VERSION 5.7 ;
BUSBITCHARS "[]" ;
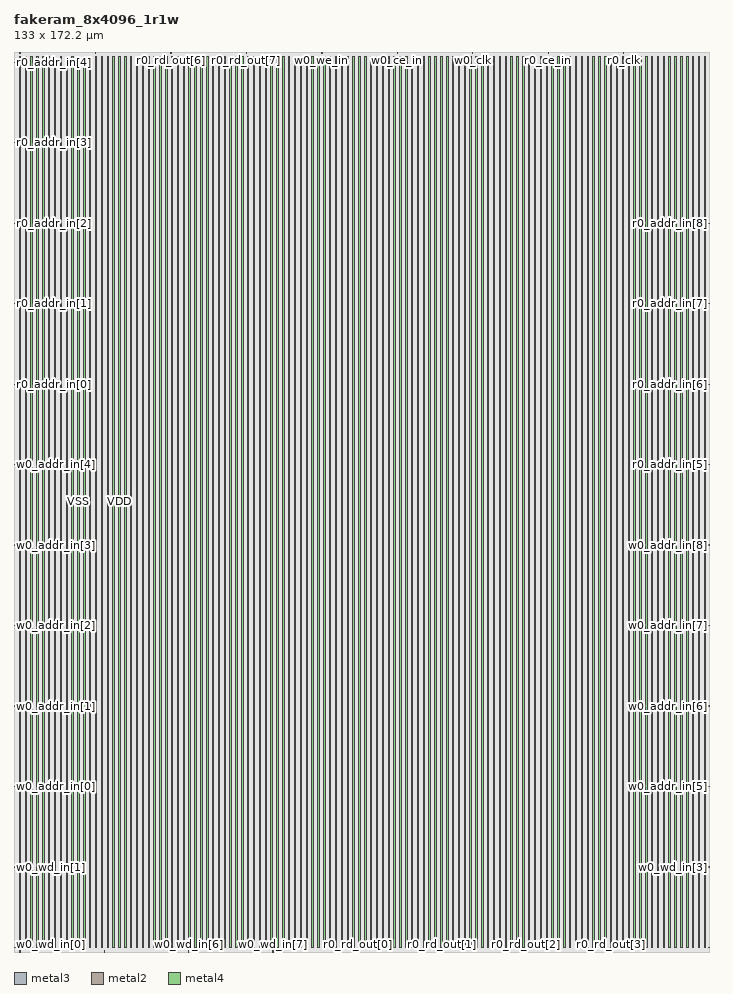
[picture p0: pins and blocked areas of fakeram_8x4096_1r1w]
MACRO fakeram_8x4096_1r1w
  FOREIGN fakeram_8x4096_1r1w 0 0 ;
  SYMMETRY X Y R90 ;
  SIZE 133.000 BY 172.200 ;
  CLASS BLOCK ;
  PIN w0_wd_in[0]
    DIRECTION INPUT ;
    USE SIGNAL ;
    SHAPE ABUTMENT ;
    PORT
      LAYER metal3 ;
      RECT 0.000 0.805 0.210 0.875 ;
    END
  END w0_wd_in[0]
  PIN w0_wd_in[1]
    DIRECTION INPUT ;
    USE SIGNAL ;
    SHAPE ABUTMENT ;
    PORT
      LAYER metal3 ;
      RECT 0.000 16.205 0.210 16.275 ;
    END
  END w0_wd_in[1]
  PIN w0_wd_in[2]
    DIRECTION INPUT ;
    USE SIGNAL ;
    SHAPE ABUTMENT ;
    PORT
      LAYER metal3 ;
      RECT 132.790 0.805 133.000 0.875 ;
    END
  END w0_wd_in[2]
  PIN w0_wd_in[3]
    DIRECTION INPUT ;
    USE SIGNAL ;
    SHAPE ABUTMENT ;
    PORT
      LAYER metal3 ;
      RECT 132.790 16.205 133.000 16.275 ;
    END
  END w0_wd_in[3]
  PIN w0_wd_in[4]
    DIRECTION INPUT ;
    USE SIGNAL ;
    SHAPE ABUTMENT ;
    PORT
      LAYER metal2 ;
      RECT 1.105 0.000 1.175 0.210 ;
    END
  END w0_wd_in[4]
  PIN w0_wd_in[5]
    DIRECTION INPUT ;
    USE SIGNAL ;
    SHAPE ABUTMENT ;
    PORT
      LAYER metal2 ;
      RECT 17.255 0.000 17.325 0.210 ;
    END
  END w0_wd_in[5]
  PIN w0_wd_in[6]
    DIRECTION INPUT ;
    USE SIGNAL ;
    SHAPE ABUTMENT ;
    PORT
      LAYER metal2 ;
      RECT 33.405 0.000 33.475 0.210 ;
    END
  END w0_wd_in[6]
  PIN w0_wd_in[7]
    DIRECTION INPUT ;
    USE SIGNAL ;
    SHAPE ABUTMENT ;
    PORT
      LAYER metal2 ;
      RECT 49.555 0.000 49.625 0.210 ;
    END
  END w0_wd_in[7]
  PIN r0_rd_out[0]
    DIRECTION OUTPUT ;
    USE SIGNAL ;
    SHAPE ABUTMENT ;
    PORT
      LAYER metal2 ;
      RECT 65.705 0.000 65.775 0.210 ;
    END
  END r0_rd_out[0]
  PIN r0_rd_out[1]
    DIRECTION OUTPUT ;
    USE SIGNAL ;
    SHAPE ABUTMENT ;
    PORT
      LAYER metal2 ;
      RECT 81.855 0.000 81.925 0.210 ;
    END
  END r0_rd_out[1]
  PIN r0_rd_out[2]
    DIRECTION OUTPUT ;
    USE SIGNAL ;
    SHAPE ABUTMENT ;
    PORT
      LAYER metal2 ;
      RECT 98.005 0.000 98.075 0.210 ;
    END
  END r0_rd_out[2]
  PIN r0_rd_out[3]
    DIRECTION OUTPUT ;
    USE SIGNAL ;
    SHAPE ABUTMENT ;
    PORT
      LAYER metal2 ;
      RECT 114.155 0.000 114.225 0.210 ;
    END
  END r0_rd_out[3]
  PIN r0_rd_out[4]
    DIRECTION OUTPUT ;
    USE SIGNAL ;
    SHAPE ABUTMENT ;
    PORT
      LAYER metal2 ;
      RECT 1.105 171.990 1.175 172.200 ;
    END
  END r0_rd_out[4]
  PIN r0_rd_out[5]
    DIRECTION OUTPUT ;
    USE SIGNAL ;
    SHAPE ABUTMENT ;
    PORT
      LAYER metal2 ;
      RECT 15.545 171.990 15.615 172.200 ;
    END
  END r0_rd_out[5]
  PIN r0_rd_out[6]
    DIRECTION OUTPUT ;
    USE SIGNAL ;
    SHAPE ABUTMENT ;
    PORT
      LAYER metal2 ;
      RECT 29.985 171.990 30.055 172.200 ;
    END
  END r0_rd_out[6]
  PIN r0_rd_out[7]
    DIRECTION OUTPUT ;
    USE SIGNAL ;
    SHAPE ABUTMENT ;
    PORT
      LAYER metal2 ;
      RECT 44.425 171.990 44.495 172.200 ;
    END
  END r0_rd_out[7]
  PIN w0_addr_in[0]
    DIRECTION INPUT ;
    USE SIGNAL ;
    SHAPE ABUTMENT ;
    PORT
      LAYER metal3 ;
      RECT 0.000 31.605 0.210 31.675 ;
    END
  END w0_addr_in[0]
  PIN w0_addr_in[1]
    DIRECTION INPUT ;
    USE SIGNAL ;
    SHAPE ABUTMENT ;
    PORT
      LAYER metal3 ;
      RECT 0.000 47.005 0.210 47.075 ;
    END
  END w0_addr_in[1]
  PIN w0_addr_in[2]
    DIRECTION INPUT ;
    USE SIGNAL ;
    SHAPE ABUTMENT ;
    PORT
      LAYER metal3 ;
      RECT 0.000 62.405 0.210 62.475 ;
    END
  END w0_addr_in[2]
  PIN w0_addr_in[3]
    DIRECTION INPUT ;
    USE SIGNAL ;
    SHAPE ABUTMENT ;
    PORT
      LAYER metal3 ;
      RECT 0.000 77.805 0.210 77.875 ;
    END
  END w0_addr_in[3]
  PIN w0_addr_in[4]
    DIRECTION INPUT ;
    USE SIGNAL ;
    SHAPE ABUTMENT ;
    PORT
      LAYER metal3 ;
      RECT 0.000 93.205 0.210 93.275 ;
    END
  END w0_addr_in[4]
  PIN w0_addr_in[5]
    DIRECTION INPUT ;
    USE SIGNAL ;
    SHAPE ABUTMENT ;
    PORT
      LAYER metal3 ;
      RECT 132.790 31.605 133.000 31.675 ;
    END
  END w0_addr_in[5]
  PIN w0_addr_in[6]
    DIRECTION INPUT ;
    USE SIGNAL ;
    SHAPE ABUTMENT ;
    PORT
      LAYER metal3 ;
      RECT 132.790 47.005 133.000 47.075 ;
    END
  END w0_addr_in[6]
  PIN w0_addr_in[7]
    DIRECTION INPUT ;
    USE SIGNAL ;
    SHAPE ABUTMENT ;
    PORT
      LAYER metal3 ;
      RECT 132.790 62.405 133.000 62.475 ;
    END
  END w0_addr_in[7]
  PIN w0_addr_in[8]
    DIRECTION INPUT ;
    USE SIGNAL ;
    SHAPE ABUTMENT ;
    PORT
      LAYER metal3 ;
      RECT 132.790 77.805 133.000 77.875 ;
    END
  END w0_addr_in[8]
  PIN r0_addr_in[0]
    DIRECTION INPUT ;
    USE SIGNAL ;
    SHAPE ABUTMENT ;
    PORT
      LAYER metal3 ;
      RECT 0.000 108.605 0.210 108.675 ;
    END
  END r0_addr_in[0]
  PIN r0_addr_in[1]
    DIRECTION INPUT ;
    USE SIGNAL ;
    SHAPE ABUTMENT ;
    PORT
      LAYER metal3 ;
      RECT 0.000 124.005 0.210 124.075 ;
    END
  END r0_addr_in[1]
  PIN r0_addr_in[2]
    DIRECTION INPUT ;
    USE SIGNAL ;
    SHAPE ABUTMENT ;
    PORT
      LAYER metal3 ;
      RECT 0.000 139.405 0.210 139.475 ;
    END
  END r0_addr_in[2]
  PIN r0_addr_in[3]
    DIRECTION INPUT ;
    USE SIGNAL ;
    SHAPE ABUTMENT ;
    PORT
      LAYER metal3 ;
      RECT 0.000 154.805 0.210 154.875 ;
    END
  END r0_addr_in[3]
  PIN r0_addr_in[4]
    DIRECTION INPUT ;
    USE SIGNAL ;
    SHAPE ABUTMENT ;
    PORT
      LAYER metal3 ;
      RECT 0.000 170.205 0.210 170.275 ;
    END
  END r0_addr_in[4]
  PIN r0_addr_in[5]
    DIRECTION INPUT ;
    USE SIGNAL ;
    SHAPE ABUTMENT ;
    PORT
      LAYER metal3 ;
      RECT 132.790 93.205 133.000 93.275 ;
    END
  END r0_addr_in[5]
  PIN r0_addr_in[6]
    DIRECTION INPUT ;
    USE SIGNAL ;
    SHAPE ABUTMENT ;
    PORT
      LAYER metal3 ;
      RECT 132.790 108.605 133.000 108.675 ;
    END
  END r0_addr_in[6]
  PIN r0_addr_in[7]
    DIRECTION INPUT ;
    USE SIGNAL ;
    SHAPE ABUTMENT ;
    PORT
      LAYER metal3 ;
      RECT 132.790 124.005 133.000 124.075 ;
    END
  END r0_addr_in[7]
  PIN r0_addr_in[8]
    DIRECTION INPUT ;
    USE SIGNAL ;
    SHAPE ABUTMENT ;
    PORT
      LAYER metal3 ;
      RECT 132.790 139.405 133.000 139.475 ;
    END
  END r0_addr_in[8]
  PIN w0_we_in
    DIRECTION INPUT ;
    USE SIGNAL ;
    SHAPE ABUTMENT ;
    PORT
      LAYER metal2 ;
      RECT 58.865 171.990 58.935 172.200 ;
    END
  END w0_we_in
  PIN w0_ce_in
    DIRECTION INPUT ;
    USE SIGNAL ;
    SHAPE ABUTMENT ;
    PORT
      LAYER metal2 ;
      RECT 73.305 171.990 73.375 172.200 ;
    END
  END w0_ce_in
  PIN w0_clk
    DIRECTION INPUT ;
    USE SIGNAL ;
    SHAPE ABUTMENT ;
    PORT
      LAYER metal2 ;
      RECT 87.745 171.990 87.815 172.200 ;
    END
  END w0_clk
  PIN r0_ce_in
    DIRECTION INPUT ;
    USE SIGNAL ;
    SHAPE ABUTMENT ;
    PORT
      LAYER metal2 ;
      RECT 102.185 171.990 102.255 172.200 ;
    END
  END r0_ce_in
  PIN r0_clk
    DIRECTION INPUT ;
    USE SIGNAL ;
    SHAPE ABUTMENT ;
    PORT
      LAYER metal2 ;
      RECT 116.625 171.990 116.695 172.200 ;
    END
  END r0_clk
  PIN VSS
    DIRECTION INOUT ;
    USE GROUND ;
    PORT
      LAYER metal4 ;
      RECT 1.000 0.840 1.280 171.360 ;
      RECT 3.240 0.840 3.520 171.360 ;
      RECT 5.480 0.840 5.760 171.360 ;
      RECT 7.720 0.840 8.000 171.360 ;
      RECT 9.960 0.840 10.240 171.360 ;
      RECT 12.200 0.840 12.480 171.360 ;
      RECT 14.440 0.840 14.720 171.360 ;
      RECT 16.680 0.840 16.960 171.360 ;
      RECT 18.920 0.840 19.200 171.360 ;
      RECT 21.160 0.840 21.440 171.360 ;
      RECT 23.400 0.840 23.680 171.360 ;
      RECT 25.640 0.840 25.920 171.360 ;
      RECT 27.880 0.840 28.160 171.360 ;
      RECT 30.120 0.840 30.400 171.360 ;
      RECT 32.360 0.840 32.640 171.360 ;
      RECT 34.600 0.840 34.880 171.360 ;
      RECT 36.840 0.840 37.120 171.360 ;
      RECT 39.080 0.840 39.360 171.360 ;
      RECT 41.320 0.840 41.600 171.360 ;
      RECT 43.560 0.840 43.840 171.360 ;
      RECT 45.800 0.840 46.080 171.360 ;
      RECT 48.040 0.840 48.320 171.360 ;
      RECT 50.280 0.840 50.560 171.360 ;
      RECT 52.520 0.840 52.800 171.360 ;
      RECT 54.760 0.840 55.040 171.360 ;
      RECT 57.000 0.840 57.280 171.360 ;
      RECT 59.240 0.840 59.520 171.360 ;
      RECT 61.480 0.840 61.760 171.360 ;
      RECT 63.720 0.840 64.000 171.360 ;
      RECT 65.960 0.840 66.240 171.360 ;
      RECT 68.200 0.840 68.480 171.360 ;
      RECT 70.440 0.840 70.720 171.360 ;
      RECT 72.680 0.840 72.960 171.360 ;
      RECT 74.920 0.840 75.200 171.360 ;
      RECT 77.160 0.840 77.440 171.360 ;
      RECT 79.400 0.840 79.680 171.360 ;
      RECT 81.640 0.840 81.920 171.360 ;
      RECT 83.880 0.840 84.160 171.360 ;
      RECT 86.120 0.840 86.400 171.360 ;
      RECT 88.360 0.840 88.640 171.360 ;
      RECT 90.600 0.840 90.880 171.360 ;
      RECT 92.840 0.840 93.120 171.360 ;
      RECT 95.080 0.840 95.360 171.360 ;
      RECT 97.320 0.840 97.600 171.360 ;
      RECT 99.560 0.840 99.840 171.360 ;
      RECT 101.800 0.840 102.080 171.360 ;
      RECT 104.040 0.840 104.320 171.360 ;
      RECT 106.280 0.840 106.560 171.360 ;
      RECT 108.520 0.840 108.800 171.360 ;
      RECT 110.760 0.840 111.040 171.360 ;
      RECT 113.000 0.840 113.280 171.360 ;
      RECT 115.240 0.840 115.520 171.360 ;
      RECT 117.480 0.840 117.760 171.360 ;
      RECT 119.720 0.840 120.000 171.360 ;
      RECT 121.960 0.840 122.240 171.360 ;
      RECT 124.200 0.840 124.480 171.360 ;
      RECT 126.440 0.840 126.720 171.360 ;
      RECT 128.680 0.840 128.960 171.360 ;
      RECT 130.920 0.840 131.200 171.360 ;
    END
  END VSS
  PIN VDD
    DIRECTION INOUT ;
    USE POWER ;
    PORT
      LAYER metal4 ;
      RECT 2.120 0.840 2.400 171.360 ;
      RECT 4.360 0.840 4.640 171.360 ;
      RECT 6.600 0.840 6.880 171.360 ;
      RECT 8.840 0.840 9.120 171.360 ;
      RECT 11.080 0.840 11.360 171.360 ;
      RECT 13.320 0.840 13.600 171.360 ;
      RECT 15.560 0.840 15.840 171.360 ;
      RECT 17.800 0.840 18.080 171.360 ;
      RECT 20.040 0.840 20.320 171.360 ;
      RECT 22.280 0.840 22.560 171.360 ;
      RECT 24.520 0.840 24.800 171.360 ;
      RECT 26.760 0.840 27.040 171.360 ;
      RECT 29.000 0.840 29.280 171.360 ;
      RECT 31.240 0.840 31.520 171.360 ;
      RECT 33.480 0.840 33.760 171.360 ;
      RECT 35.720 0.840 36.000 171.360 ;
      RECT 37.960 0.840 38.240 171.360 ;
      RECT 40.200 0.840 40.480 171.360 ;
      RECT 42.440 0.840 42.720 171.360 ;
      RECT 44.680 0.840 44.960 171.360 ;
      RECT 46.920 0.840 47.200 171.360 ;
      RECT 49.160 0.840 49.440 171.360 ;
      RECT 51.400 0.840 51.680 171.360 ;
      RECT 53.640 0.840 53.920 171.360 ;
      RECT 55.880 0.840 56.160 171.360 ;
      RECT 58.120 0.840 58.400 171.360 ;
      RECT 60.360 0.840 60.640 171.360 ;
      RECT 62.600 0.840 62.880 171.360 ;
      RECT 64.840 0.840 65.120 171.360 ;
      RECT 67.080 0.840 67.360 171.360 ;
      RECT 69.320 0.840 69.600 171.360 ;
      RECT 71.560 0.840 71.840 171.360 ;
      RECT 73.800 0.840 74.080 171.360 ;
      RECT 76.040 0.840 76.320 171.360 ;
      RECT 78.280 0.840 78.560 171.360 ;
      RECT 80.520 0.840 80.800 171.360 ;
      RECT 82.760 0.840 83.040 171.360 ;
      RECT 85.000 0.840 85.280 171.360 ;
      RECT 87.240 0.840 87.520 171.360 ;
      RECT 89.480 0.840 89.760 171.360 ;
      RECT 91.720 0.840 92.000 171.360 ;
      RECT 93.960 0.840 94.240 171.360 ;
      RECT 96.200 0.840 96.480 171.360 ;
      RECT 98.440 0.840 98.720 171.360 ;
      RECT 100.680 0.840 100.960 171.360 ;
      RECT 102.920 0.840 103.200 171.360 ;
      RECT 105.160 0.840 105.440 171.360 ;
      RECT 107.400 0.840 107.680 171.360 ;
      RECT 109.640 0.840 109.920 171.360 ;
      RECT 111.880 0.840 112.160 171.360 ;
      RECT 114.120 0.840 114.400 171.360 ;
      RECT 116.360 0.840 116.640 171.360 ;
      RECT 118.600 0.840 118.880 171.360 ;
      RECT 120.840 0.840 121.120 171.360 ;
      RECT 123.080 0.840 123.360 171.360 ;
      RECT 125.320 0.840 125.600 171.360 ;
      RECT 127.560 0.840 127.840 171.360 ;
      RECT 129.800 0.840 130.080 171.360 ;
      RECT 132.040 0.840 132.320 171.360 ;
    END
  END VDD
  OBS
    LAYER metal1 ;
    RECT 0 0 133.000 172.200 ;
    LAYER metal2 ;
    RECT 0 0 133.000 172.200 ;
    LAYER metal3 ;
    RECT 0 0 133.000 172.200 ;
    LAYER metal4 ;
    RECT 0 0 133.000 172.200 ;
    LAYER OVERLAP ;
    RECT 0 0 133.000 172.200 ;
  END
END fakeram_8x4096_1r1w

END LIBRARY
